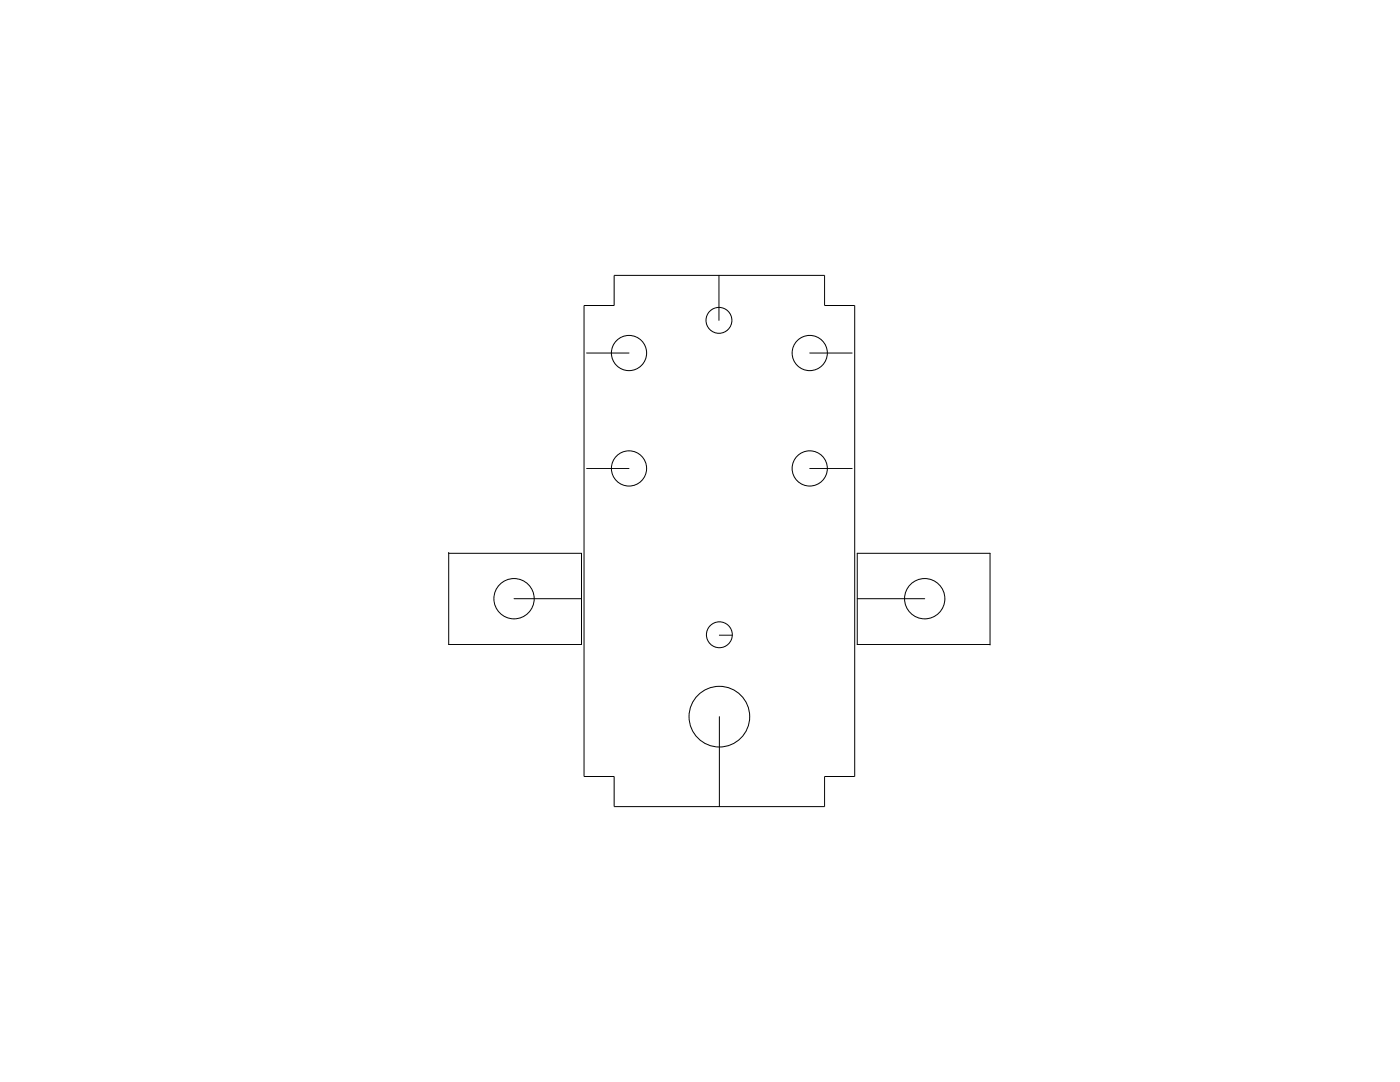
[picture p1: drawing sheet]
<svg xmlns="http://www.w3.org/2000/svg" width="279mm" height="216mm" viewBox="0 0 279 216" stroke-linecap="round" stroke-linejoin="round" font-family="sans-serif">
<g fill="none" stroke="#000" stroke-width=".2">
<path d="M143.5 54.9v9M116.6 61h6v-6.1h42v6.1h6v93.9h-6v6.1h-42v-6.1h-6zM117.1 70.4h8.4M161.6 70.4h8.5M117.1 93.5h8.4M161.6 93.5h8.5M89.5 110.2v18.4h26.5v-18.2h-26.5M102.6 119.5h13.4M171.1 119.5h13.4M143.6 126.7h2.5M197.6 128.6h-26.5v-18.2h26.5v18.3M143.6 143v18"/>
<circle cx="125.5" cy="70.4" r="3.5"/>
<circle cx="143.5" cy="63.9" r="2.58"/>
<circle cx="161.6" cy="70.4" r="3.5"/>
<circle cx="125.5" cy="93.5" r="3.5"/>
<circle cx="161.6" cy="93.5" r="3.5"/>
<circle cx="102.6" cy="119.5" r="4"/>
<circle cx="184.5" cy="119.5" r="4"/>
<circle cx="143.6" cy="126.7" r="2.58"/>
<circle cx="143.6" cy="143" r="6.1"/>
</g>
</svg>
